VERSION 5.7 ;
  NOWIREEXTENSIONATPIN ON ;
  DIVIDERCHAR "/" ;
  BUSBITCHARS "[]" ;
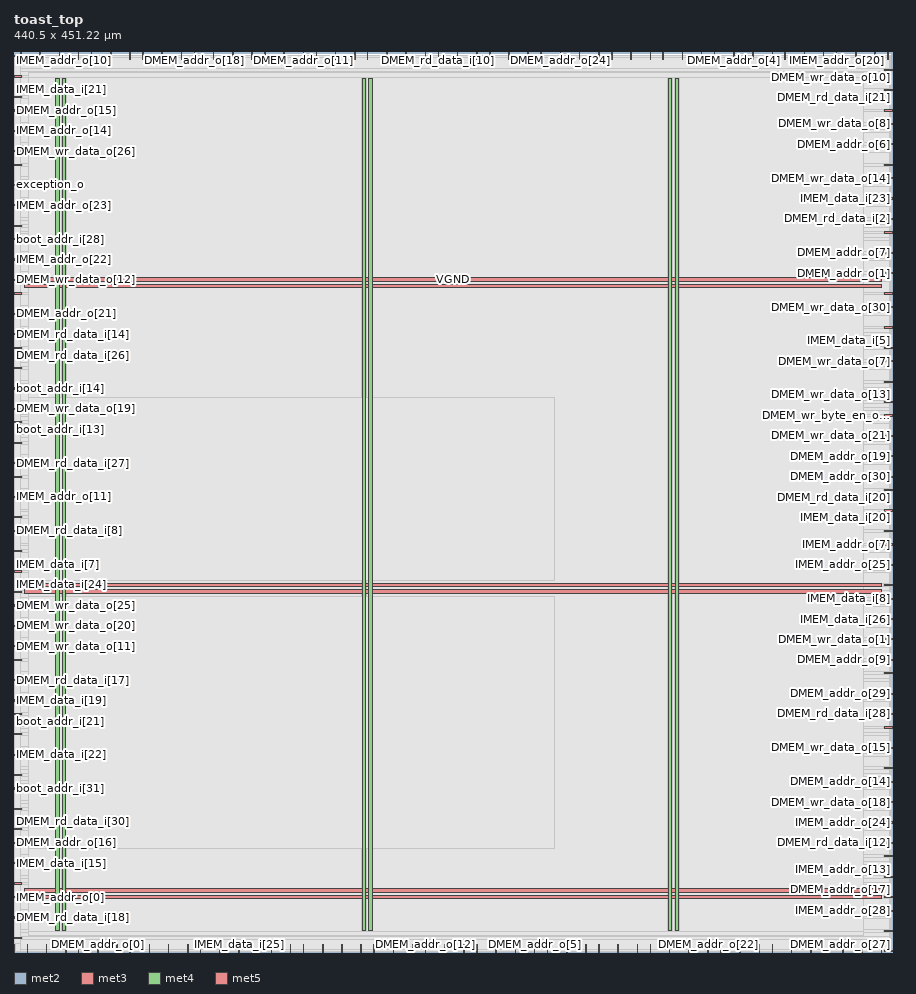
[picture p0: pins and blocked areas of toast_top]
MACRO toast_top
  CLASS BLOCK ;
  FOREIGN toast_top ;
  ORIGIN 0.000 0.000 ;
  SIZE 440.500 BY 451.220 ;
  PIN DMEM_addr_o[0]
    DIRECTION OUTPUT TRISTATE ;
    USE SIGNAL ;
    PORT
      LAYER met2 ;
        RECT 41.950 0.000 42.230 4.000 ;
    END
  END DMEM_addr_o[0]
  PIN DMEM_addr_o[10]
    DIRECTION OUTPUT TRISTATE ;
    USE SIGNAL ;
    PORT
      LAYER met2 ;
        RECT 177.190 447.220 177.470 451.220 ;
    END
  END DMEM_addr_o[10]
  PIN DMEM_addr_o[11]
    DIRECTION OUTPUT TRISTATE ;
    USE SIGNAL ;
    PORT
      LAYER met2 ;
        RECT 144.990 447.220 145.270 451.220 ;
    END
  END DMEM_addr_o[11]
  PIN DMEM_addr_o[12]
    DIRECTION OUTPUT TRISTATE ;
    USE SIGNAL ;
    PORT
      LAYER met2 ;
        RECT 206.170 0.000 206.450 4.000 ;
    END
  END DMEM_addr_o[12]
  PIN DMEM_addr_o[13]
    DIRECTION OUTPUT TRISTATE ;
    USE SIGNAL ;
    PORT
      LAYER met2 ;
        RECT 363.950 0.000 364.230 4.000 ;
    END
  END DMEM_addr_o[13]
  PIN DMEM_addr_o[14]
    DIRECTION OUTPUT TRISTATE ;
    USE SIGNAL ;
    PORT
      LAYER met3 ;
        RECT 436.500 85.040 440.500 85.640 ;
    END
  END DMEM_addr_o[14]
  PIN DMEM_addr_o[15]
    DIRECTION OUTPUT TRISTATE ;
    USE SIGNAL ;
    PORT
      LAYER met3 ;
        RECT 0.000 421.640 4.000 422.240 ;
    END
  END DMEM_addr_o[15]
  PIN DMEM_addr_o[16]
    DIRECTION OUTPUT TRISTATE ;
    USE SIGNAL ;
    PORT
      LAYER met3 ;
        RECT 0.000 54.440 4.000 55.040 ;
    END
  END DMEM_addr_o[16]
  PIN DMEM_addr_o[17]
    DIRECTION OUTPUT TRISTATE ;
    USE SIGNAL ;
    PORT
      LAYER met3 ;
        RECT 436.500 27.240 440.500 27.840 ;
    END
  END DMEM_addr_o[17]
  PIN DMEM_addr_o[18]
    DIRECTION OUTPUT TRISTATE ;
    USE SIGNAL ;
    PORT
      LAYER met2 ;
        RECT 90.250 447.220 90.530 451.220 ;
    END
  END DMEM_addr_o[18]
  PIN DMEM_addr_o[19]
    DIRECTION OUTPUT TRISTATE ;
    USE SIGNAL ;
    PORT
      LAYER met3 ;
        RECT 436.500 248.240 440.500 248.840 ;
    END
  END DMEM_addr_o[19]
  PIN DMEM_addr_o[1]
    DIRECTION OUTPUT TRISTATE ;
    USE SIGNAL ;
    PORT
      LAYER met3 ;
        RECT 436.500 340.040 440.500 340.640 ;
    END
  END DMEM_addr_o[1]
  PIN DMEM_addr_o[20]
    DIRECTION OUTPUT TRISTATE ;
    USE SIGNAL ;
    PORT
      LAYER met2 ;
        RECT 338.190 0.000 338.470 4.000 ;
    END
  END DMEM_addr_o[20]
  PIN DMEM_addr_o[21]
    DIRECTION OUTPUT TRISTATE ;
    USE SIGNAL ;
    PORT
      LAYER met3 ;
        RECT 0.000 319.640 4.000 320.240 ;
    END
  END DMEM_addr_o[21]
  PIN DMEM_addr_o[22]
    DIRECTION OUTPUT TRISTATE ;
    USE SIGNAL ;
    PORT
      LAYER met2 ;
        RECT 347.850 0.000 348.130 4.000 ;
    END
  END DMEM_addr_o[22]
  PIN DMEM_addr_o[23]
    DIRECTION OUTPUT TRISTATE ;
    USE SIGNAL ;
    PORT
      LAYER met2 ;
        RECT 144.990 0.000 145.270 4.000 ;
    END
  END DMEM_addr_o[23]
  PIN DMEM_addr_o[24]
    DIRECTION OUTPUT TRISTATE ;
    USE SIGNAL ;
    PORT
      LAYER met2 ;
        RECT 273.790 447.220 274.070 451.220 ;
    END
  END DMEM_addr_o[24]
  PIN DMEM_addr_o[25]
    DIRECTION OUTPUT TRISTATE ;
    USE SIGNAL ;
    PORT
      LAYER met3 ;
        RECT 0.000 394.440 4.000 395.040 ;
    END
  END DMEM_addr_o[25]
  PIN DMEM_addr_o[26]
    DIRECTION OUTPUT TRISTATE ;
    USE SIGNAL ;
    PORT
      LAYER met2 ;
        RECT 431.570 447.220 431.850 451.220 ;
    END
  END DMEM_addr_o[26]
  PIN DMEM_addr_o[27]
    DIRECTION OUTPUT TRISTATE ;
    USE SIGNAL ;
    PORT
      LAYER met2 ;
        RECT 415.470 0.000 415.750 4.000 ;
    END
  END DMEM_addr_o[27]
  PIN DMEM_addr_o[28]
    DIRECTION OUTPUT TRISTATE ;
    USE SIGNAL ;
    PORT
      LAYER met2 ;
        RECT 135.330 447.220 135.610 451.220 ;
    END
  END DMEM_addr_o[28]
  PIN DMEM_addr_o[29]
    DIRECTION OUTPUT TRISTATE ;
    USE SIGNAL ;
    PORT
      LAYER met3 ;
        RECT 436.500 129.240 440.500 129.840 ;
    END
  END DMEM_addr_o[29]
  PIN DMEM_addr_o[2]
    DIRECTION OUTPUT TRISTATE ;
    USE SIGNAL ;
    PORT
      LAYER met2 ;
        RECT 277.010 0.000 277.290 4.000 ;
    END
  END DMEM_addr_o[2]
  PIN DMEM_addr_o[30]
    DIRECTION OUTPUT TRISTATE ;
    USE SIGNAL ;
    PORT
      LAYER met3 ;
        RECT 436.500 238.040 440.500 238.640 ;
    END
  END DMEM_addr_o[30]
  PIN DMEM_addr_o[31]
    DIRECTION OUTPUT TRISTATE ;
    USE SIGNAL ;
    PORT
      LAYER met2 ;
        RECT 83.810 447.220 84.090 451.220 ;
    END
  END DMEM_addr_o[31]
  PIN DMEM_addr_o[3]
    DIRECTION OUTPUT TRISTATE ;
    USE SIGNAL ;
    PORT
      LAYER met2 ;
        RECT 22.630 447.220 22.910 451.220 ;
    END
  END DMEM_addr_o[3]
  PIN DMEM_addr_o[4]
    DIRECTION OUTPUT TRISTATE ;
    USE SIGNAL ;
    PORT
      LAYER met2 ;
        RECT 360.730 447.220 361.010 451.220 ;
    END
  END DMEM_addr_o[4]
  PIN DMEM_addr_o[5]
    DIRECTION OUTPUT TRISTATE ;
    USE SIGNAL ;
    PORT
      LAYER met2 ;
        RECT 260.910 0.000 261.190 4.000 ;
    END
  END DMEM_addr_o[5]
  PIN DMEM_addr_o[6]
    DIRECTION OUTPUT TRISTATE ;
    USE SIGNAL ;
    PORT
      LAYER met3 ;
        RECT 436.500 404.640 440.500 405.240 ;
    END
  END DMEM_addr_o[6]
  PIN DMEM_addr_o[7]
    DIRECTION OUTPUT TRISTATE ;
    USE SIGNAL ;
    PORT
      LAYER met3 ;
        RECT 436.500 350.240 440.500 350.840 ;
    END
  END DMEM_addr_o[7]
  PIN DMEM_addr_o[8]
    DIRECTION OUTPUT TRISTATE ;
    USE SIGNAL ;
    PORT
      LAYER met3 ;
        RECT 436.500 183.640 440.500 184.240 ;
    END
  END DMEM_addr_o[8]
  PIN DMEM_addr_o[9]
    DIRECTION OUTPUT TRISTATE ;
    USE SIGNAL ;
    PORT
      LAYER met3 ;
        RECT 436.500 146.240 440.500 146.840 ;
    END
  END DMEM_addr_o[9]
  PIN DMEM_rd_data_i[0]
    DIRECTION INPUT ;
    USE SIGNAL ;
    PORT
      LAYER met2 ;
        RECT 161.090 447.220 161.370 451.220 ;
    END
  END DMEM_rd_data_i[0]
  PIN DMEM_rd_data_i[10]
    DIRECTION INPUT ;
    USE SIGNAL ;
    PORT
      LAYER met2 ;
        RECT 212.610 447.220 212.890 451.220 ;
    END
  END DMEM_rd_data_i[10]
  PIN DMEM_rd_data_i[11]
    DIRECTION INPUT ;
    USE SIGNAL ;
    PORT
      LAYER met2 ;
        RECT 386.490 447.220 386.770 451.220 ;
    END
  END DMEM_rd_data_i[11]
  PIN DMEM_rd_data_i[12]
    DIRECTION INPUT ;
    USE SIGNAL ;
    PORT
      LAYER met3 ;
        RECT 436.500 54.440 440.500 55.040 ;
    END
  END DMEM_rd_data_i[12]
  PIN DMEM_rd_data_i[13]
    DIRECTION INPUT ;
    USE SIGNAL ;
    PORT
      LAYER met2 ;
        RECT 325.310 447.220 325.590 451.220 ;
    END
  END DMEM_rd_data_i[13]
  PIN DMEM_rd_data_i[14]
    DIRECTION INPUT ;
    USE SIGNAL ;
    PORT
      LAYER met3 ;
        RECT 0.000 309.440 4.000 310.040 ;
    END
  END DMEM_rd_data_i[14]
  PIN DMEM_rd_data_i[15]
    DIRECTION INPUT ;
    USE SIGNAL ;
    PORT
      LAYER met2 ;
        RECT 380.050 447.220 380.330 451.220 ;
    END
  END DMEM_rd_data_i[15]
  PIN DMEM_rd_data_i[16]
    DIRECTION INPUT ;
    USE SIGNAL ;
    PORT
      LAYER met2 ;
        RECT 293.110 0.000 293.390 4.000 ;
    END
  END DMEM_rd_data_i[16]
  PIN DMEM_rd_data_i[17]
    DIRECTION INPUT ;
    USE SIGNAL ;
    PORT
      LAYER met3 ;
        RECT 0.000 136.040 4.000 136.640 ;
    END
  END DMEM_rd_data_i[17]
  PIN DMEM_rd_data_i[18]
    DIRECTION INPUT ;
    USE SIGNAL ;
    PORT
      LAYER met3 ;
        RECT 0.000 17.040 4.000 17.640 ;
    END
  END DMEM_rd_data_i[18]
  PIN DMEM_rd_data_i[19]
    DIRECTION INPUT ;
    USE SIGNAL ;
    PORT
      LAYER met2 ;
        RECT 231.930 0.000 232.210 4.000 ;
    END
  END DMEM_rd_data_i[19]
  PIN DMEM_rd_data_i[1]
    DIRECTION INPUT ;
    USE SIGNAL ;
    PORT
      LAYER met2 ;
        RECT 128.890 0.000 129.170 4.000 ;
    END
  END DMEM_rd_data_i[1]
  PIN DMEM_rd_data_i[20]
    DIRECTION INPUT ;
    USE SIGNAL ;
    PORT
      LAYER met3 ;
        RECT 436.500 231.240 440.500 231.840 ;
    END
  END DMEM_rd_data_i[20]
  PIN DMEM_rd_data_i[21]
    DIRECTION INPUT ;
    USE SIGNAL ;
    PORT
      LAYER met3 ;
        RECT 436.500 431.840 440.500 432.440 ;
    END
  END DMEM_rd_data_i[21]
  PIN DMEM_rd_data_i[22]
    DIRECTION INPUT ;
    USE SIGNAL ;
    PORT
      LAYER met2 ;
        RECT 344.630 447.220 344.910 451.220 ;
    END
  END DMEM_rd_data_i[22]
  PIN DMEM_rd_data_i[23]
    DIRECTION INPUT ;
    USE SIGNAL ;
    PORT
      LAYER met3 ;
        RECT 0.000 448.840 4.000 449.440 ;
    END
  END DMEM_rd_data_i[23]
  PIN DMEM_rd_data_i[24]
    DIRECTION INPUT ;
    USE SIGNAL ;
    PORT
      LAYER met2 ;
        RECT 170.750 447.220 171.030 451.220 ;
    END
  END DMEM_rd_data_i[24]
  PIN DMEM_rd_data_i[25]
    DIRECTION INPUT ;
    USE SIGNAL ;
    PORT
      LAYER met2 ;
        RECT 434.790 0.000 435.070 4.000 ;
    END
  END DMEM_rd_data_i[25]
  PIN DMEM_rd_data_i[26]
    DIRECTION INPUT ;
    USE SIGNAL ;
    PORT
      LAYER met3 ;
        RECT 0.000 302.640 4.000 303.240 ;
    END
  END DMEM_rd_data_i[26]
  PIN DMEM_rd_data_i[27]
    DIRECTION INPUT ;
    USE SIGNAL ;
    PORT
      LAYER met3 ;
        RECT 0.000 244.840 4.000 245.440 ;
    END
  END DMEM_rd_data_i[27]
  PIN DMEM_rd_data_i[28]
    DIRECTION INPUT ;
    USE SIGNAL ;
    PORT
      LAYER met3 ;
        RECT 436.500 119.040 440.500 119.640 ;
    END
  END DMEM_rd_data_i[28]
  PIN DMEM_rd_data_i[29]
    DIRECTION INPUT ;
    USE SIGNAL ;
    PORT
      LAYER met3 ;
        RECT 0.000 6.840 4.000 7.440 ;
    END
  END DMEM_rd_data_i[29]
  PIN DMEM_rd_data_i[2]
    DIRECTION INPUT ;
    USE SIGNAL ;
    PORT
      LAYER met3 ;
        RECT 436.500 367.240 440.500 367.840 ;
    END
  END DMEM_rd_data_i[2]
  PIN DMEM_rd_data_i[30]
    DIRECTION INPUT ;
    USE SIGNAL ;
    PORT
      LAYER met3 ;
        RECT 0.000 61.240 4.000 61.840 ;
    END
  END DMEM_rd_data_i[30]
  PIN DMEM_rd_data_i[31]
    DIRECTION INPUT ;
    USE SIGNAL ;
    PORT
      LAYER met2 ;
        RECT 99.910 447.220 100.190 451.220 ;
    END
  END DMEM_rd_data_i[31]
  PIN DMEM_rd_data_i[3]
    DIRECTION INPUT ;
    USE SIGNAL ;
    PORT
      LAYER met2 ;
        RECT 93.470 0.000 93.750 4.000 ;
    END
  END DMEM_rd_data_i[3]
  PIN DMEM_rd_data_i[4]
    DIRECTION INPUT ;
    USE SIGNAL ;
    PORT
      LAYER met2 ;
        RECT 119.230 447.220 119.510 451.220 ;
    END
  END DMEM_rd_data_i[4]
  PIN DMEM_rd_data_i[5]
    DIRECTION INPUT ;
    USE SIGNAL ;
    PORT
      LAYER met2 ;
        RECT 399.370 0.000 399.650 4.000 ;
    END
  END DMEM_rd_data_i[5]
  PIN DMEM_rd_data_i[6]
    DIRECTION INPUT ;
    USE SIGNAL ;
    PORT
      LAYER met2 ;
        RECT 215.830 0.000 216.110 4.000 ;
    END
  END DMEM_rd_data_i[6]
  PIN DMEM_rd_data_i[7]
    DIRECTION INPUT ;
    USE SIGNAL ;
    PORT
      LAYER met2 ;
        RECT 125.670 447.220 125.950 451.220 ;
    END
  END DMEM_rd_data_i[7]
  PIN DMEM_rd_data_i[8]
    DIRECTION INPUT ;
    USE SIGNAL ;
    PORT
      LAYER met3 ;
        RECT 0.000 210.840 4.000 211.440 ;
    END
  END DMEM_rd_data_i[8]
  PIN DMEM_rd_data_i[9]
    DIRECTION INPUT ;
    USE SIGNAL ;
    PORT
      LAYER met2 ;
        RECT 32.290 0.000 32.570 4.000 ;
    END
  END DMEM_rd_data_i[9]
  PIN DMEM_rst_o
    DIRECTION OUTPUT TRISTATE ;
    USE SIGNAL ;
    PORT
      LAYER met3 ;
        RECT 0.000 200.640 4.000 201.240 ;
    END
  END DMEM_rst_o
  PIN DMEM_wr_byte_en_o[0]
    DIRECTION OUTPUT TRISTATE ;
    USE SIGNAL ;
    PORT
      LAYER met3 ;
        RECT 436.500 10.240 440.500 10.840 ;
    END
  END DMEM_wr_byte_en_o[0]
  PIN DMEM_wr_byte_en_o[1]
    DIRECTION OUTPUT TRISTATE ;
    USE SIGNAL ;
    PORT
      LAYER met3 ;
        RECT 436.500 268.640 440.500 269.240 ;
    END
  END DMEM_wr_byte_en_o[1]
  PIN DMEM_wr_byte_en_o[2]
    DIRECTION OUTPUT TRISTATE ;
    USE SIGNAL ;
    PORT
      LAYER met2 ;
        RECT 77.370 0.000 77.650 4.000 ;
    END
  END DMEM_wr_byte_en_o[2]
  PIN DMEM_wr_byte_en_o[3]
    DIRECTION OUTPUT TRISTATE ;
    USE SIGNAL ;
    PORT
      LAYER met2 ;
        RECT 318.870 447.220 319.150 451.220 ;
    END
  END DMEM_wr_byte_en_o[3]
  PIN DMEM_wr_data_o[0]
    DIRECTION OUTPUT TRISTATE ;
    USE SIGNAL ;
    PORT
      LAYER met2 ;
        RECT 109.570 447.220 109.850 451.220 ;
    END
  END DMEM_wr_data_o[0]
  PIN DMEM_wr_data_o[10]
    DIRECTION OUTPUT TRISTATE ;
    USE SIGNAL ;
    PORT
      LAYER met3 ;
        RECT 436.500 442.040 440.500 442.640 ;
    END
  END DMEM_wr_data_o[10]
  PIN DMEM_wr_data_o[11]
    DIRECTION OUTPUT TRISTATE ;
    USE SIGNAL ;
    PORT
      LAYER met3 ;
        RECT 0.000 153.040 4.000 153.640 ;
    END
  END DMEM_wr_data_o[11]
  PIN DMEM_wr_data_o[12]
    DIRECTION OUTPUT TRISTATE ;
    USE SIGNAL ;
    PORT
      LAYER met3 ;
        RECT 0.000 336.640 4.000 337.240 ;
    END
  END DMEM_wr_data_o[12]
  PIN DMEM_wr_data_o[13]
    DIRECTION OUTPUT TRISTATE ;
    USE SIGNAL ;
    PORT
      LAYER met3 ;
        RECT 436.500 275.440 440.500 276.040 ;
    END
  END DMEM_wr_data_o[13]
  PIN DMEM_wr_data_o[14]
    DIRECTION OUTPUT TRISTATE ;
    USE SIGNAL ;
    PORT
      LAYER met3 ;
        RECT 436.500 387.640 440.500 388.240 ;
    END
  END DMEM_wr_data_o[14]
  PIN DMEM_wr_data_o[15]
    DIRECTION OUTPUT TRISTATE ;
    USE SIGNAL ;
    PORT
      LAYER met3 ;
        RECT 436.500 102.040 440.500 102.640 ;
    END
  END DMEM_wr_data_o[15]
  PIN DMEM_wr_data_o[16]
    DIRECTION OUTPUT TRISTATE ;
    USE SIGNAL ;
    PORT
      LAYER met2 ;
        RECT 354.290 0.000 354.570 4.000 ;
    END
  END DMEM_wr_data_o[16]
  PIN DMEM_wr_data_o[17]
    DIRECTION OUTPUT TRISTATE ;
    USE SIGNAL ;
    PORT
      LAYER met3 ;
        RECT 0.000 292.440 4.000 293.040 ;
    END
  END DMEM_wr_data_o[17]
  PIN DMEM_wr_data_o[18]
    DIRECTION OUTPUT TRISTATE ;
    USE SIGNAL ;
    PORT
      LAYER met3 ;
        RECT 436.500 74.840 440.500 75.440 ;
    END
  END DMEM_wr_data_o[18]
  PIN DMEM_wr_data_o[19]
    DIRECTION OUTPUT TRISTATE ;
    USE SIGNAL ;
    PORT
      LAYER met3 ;
        RECT 0.000 272.040 4.000 272.640 ;
    END
  END DMEM_wr_data_o[19]
  PIN DMEM_wr_data_o[1]
    DIRECTION OUTPUT TRISTATE ;
    USE SIGNAL ;
    PORT
      LAYER met3 ;
        RECT 436.500 156.440 440.500 157.040 ;
    END
  END DMEM_wr_data_o[1]
  PIN DMEM_wr_data_o[20]
    DIRECTION OUTPUT TRISTATE ;
    USE SIGNAL ;
    PORT
      LAYER met3 ;
        RECT 0.000 163.240 4.000 163.840 ;
    END
  END DMEM_wr_data_o[20]
  PIN DMEM_wr_data_o[21]
    DIRECTION OUTPUT TRISTATE ;
    USE SIGNAL ;
    PORT
      LAYER met3 ;
        RECT 436.500 258.440 440.500 259.040 ;
    END
  END DMEM_wr_data_o[21]
  PIN DMEM_wr_data_o[22]
    DIRECTION OUTPUT TRISTATE ;
    USE SIGNAL ;
    PORT
      LAYER met2 ;
        RECT 438.010 447.220 438.290 451.220 ;
    END
  END DMEM_wr_data_o[22]
  PIN DMEM_wr_data_o[23]
    DIRECTION OUTPUT TRISTATE ;
    USE SIGNAL ;
    PORT
      LAYER met2 ;
        RECT 334.970 447.220 335.250 451.220 ;
    END
  END DMEM_wr_data_o[23]
  PIN DMEM_wr_data_o[24]
    DIRECTION OUTPUT TRISTATE ;
    USE SIGNAL ;
    PORT
      LAYER met2 ;
        RECT 138.550 0.000 138.830 4.000 ;
    END
  END DMEM_wr_data_o[24]
  PIN DMEM_wr_data_o[25]
    DIRECTION OUTPUT TRISTATE ;
    USE SIGNAL ;
    PORT
      LAYER met3 ;
        RECT 0.000 173.440 4.000 174.040 ;
    END
  END DMEM_wr_data_o[25]
  PIN DMEM_wr_data_o[26]
    DIRECTION OUTPUT TRISTATE ;
    USE SIGNAL ;
    PORT
      LAYER met3 ;
        RECT 0.000 401.240 4.000 401.840 ;
    END
  END DMEM_wr_data_o[26]
  PIN DMEM_wr_data_o[27]
    DIRECTION OUTPUT TRISTATE ;
    USE SIGNAL ;
    PORT
      LAYER met2 ;
        RECT 248.030 447.220 248.310 451.220 ;
    END
  END DMEM_wr_data_o[27]
  PIN DMEM_wr_data_o[28]
    DIRECTION OUTPUT TRISTATE ;
    USE SIGNAL ;
    PORT
      LAYER met2 ;
        RECT 370.390 447.220 370.670 451.220 ;
    END
  END DMEM_wr_data_o[28]
  PIN DMEM_wr_data_o[29]
    DIRECTION OUTPUT TRISTATE ;
    USE SIGNAL ;
    PORT
      LAYER met2 ;
        RECT 58.050 447.220 58.330 451.220 ;
    END
  END DMEM_wr_data_o[29]
  PIN DMEM_wr_data_o[2]
    DIRECTION OUTPUT TRISTATE ;
    USE SIGNAL ;
    PORT
      LAYER met2 ;
        RECT 186.850 447.220 187.130 451.220 ;
    END
  END DMEM_wr_data_o[2]
  PIN DMEM_wr_data_o[30]
    DIRECTION OUTPUT TRISTATE ;
    USE SIGNAL ;
    PORT
      LAYER met3 ;
        RECT 436.500 323.040 440.500 323.640 ;
    END
  END DMEM_wr_data_o[30]
  PIN DMEM_wr_data_o[31]
    DIRECTION OUTPUT TRISTATE ;
    USE SIGNAL ;
    PORT
      LAYER met2 ;
        RECT 238.370 447.220 238.650 451.220 ;
    END
  END DMEM_wr_data_o[31]
  PIN DMEM_wr_data_o[3]
    DIRECTION OUTPUT TRISTATE ;
    USE SIGNAL ;
    PORT
      LAYER met2 ;
        RECT 318.870 0.000 319.150 4.000 ;
    END
  END DMEM_wr_data_o[3]
  PIN DMEM_wr_data_o[4]
    DIRECTION OUTPUT TRISTATE ;
    USE SIGNAL ;
    PORT
      LAYER met3 ;
        RECT 436.500 360.440 440.500 361.040 ;
    END
  END DMEM_wr_data_o[4]
  PIN DMEM_wr_data_o[5]
    DIRECTION OUTPUT TRISTATE ;
    USE SIGNAL ;
    PORT
      LAYER met2 ;
        RECT 373.610 0.000 373.890 4.000 ;
    END
  END DMEM_wr_data_o[5]
  PIN DMEM_wr_data_o[6]
    DIRECTION OUTPUT TRISTATE ;
    USE SIGNAL ;
    PORT
      LAYER met2 ;
        RECT 48.390 447.220 48.670 451.220 ;
    END
  END DMEM_wr_data_o[6]
  PIN DMEM_wr_data_o[7]
    DIRECTION OUTPUT TRISTATE ;
    USE SIGNAL ;
    PORT
      LAYER met3 ;
        RECT 436.500 295.840 440.500 296.440 ;
    END
  END DMEM_wr_data_o[7]
  PIN DMEM_wr_data_o[8]
    DIRECTION OUTPUT TRISTATE ;
    USE SIGNAL ;
    PORT
      LAYER met3 ;
        RECT 436.500 414.840 440.500 415.440 ;
    END
  END DMEM_wr_data_o[8]
  PIN DMEM_wr_data_o[9]
    DIRECTION OUTPUT TRISTATE ;
    USE SIGNAL ;
    PORT
      LAYER met3 ;
        RECT 0.000 71.440 4.000 72.040 ;
    END
  END DMEM_wr_data_o[9]
  PIN IMEM_addr_o[0]
    DIRECTION OUTPUT TRISTATE ;
    USE SIGNAL ;
    PORT
      LAYER met3 ;
        RECT 0.000 27.240 4.000 27.840 ;
    END
  END IMEM_addr_o[0]
  PIN IMEM_addr_o[10]
    DIRECTION OUTPUT TRISTATE ;
    USE SIGNAL ;
    PORT
      LAYER met2 ;
        RECT 12.970 447.220 13.250 451.220 ;
    END
  END IMEM_addr_o[10]
  PIN IMEM_addr_o[11]
    DIRECTION OUTPUT TRISTATE ;
    USE SIGNAL ;
    PORT
      LAYER met3 ;
        RECT 0.000 227.840 4.000 228.440 ;
    END
  END IMEM_addr_o[11]
  PIN IMEM_addr_o[12]
    DIRECTION OUTPUT TRISTATE ;
    USE SIGNAL ;
    PORT
      LAYER met2 ;
        RECT 180.410 0.000 180.690 4.000 ;
    END
  END IMEM_addr_o[12]
  PIN IMEM_addr_o[13]
    DIRECTION OUTPUT TRISTATE ;
    USE SIGNAL ;
    PORT
      LAYER met3 ;
        RECT 436.500 37.440 440.500 38.040 ;
    END
  END IMEM_addr_o[13]
  PIN IMEM_addr_o[14]
    DIRECTION OUTPUT TRISTATE ;
    USE SIGNAL ;
    PORT
      LAYER met3 ;
        RECT 0.000 411.440 4.000 412.040 ;
    END
  END IMEM_addr_o[14]
  PIN IMEM_addr_o[15]
    DIRECTION OUTPUT TRISTATE ;
    USE SIGNAL ;
    PORT
      LAYER met2 ;
        RECT 286.670 0.000 286.950 4.000 ;
    END
  END IMEM_addr_o[15]
  PIN IMEM_addr_o[16]
    DIRECTION OUTPUT TRISTATE ;
    USE SIGNAL ;
    PORT
      LAYER met2 ;
        RECT 264.130 447.220 264.410 451.220 ;
    END
  END IMEM_addr_o[16]
  PIN IMEM_addr_o[17]
    DIRECTION OUTPUT TRISTATE ;
    USE SIGNAL ;
    PORT
      LAYER met2 ;
        RECT 283.450 447.220 283.730 451.220 ;
    END
  END IMEM_addr_o[17]
  PIN IMEM_addr_o[18]
    DIRECTION OUTPUT TRISTATE ;
    USE SIGNAL ;
    PORT
      LAYER met2 ;
        RECT 173.970 0.000 174.250 4.000 ;
    END
  END IMEM_addr_o[18]
  PIN IMEM_addr_o[19]
    DIRECTION OUTPUT TRISTATE ;
    USE SIGNAL ;
    PORT
      LAYER met2 ;
        RECT 231.930 447.220 232.210 451.220 ;
    END
  END IMEM_addr_o[19]
  PIN IMEM_addr_o[1]
    DIRECTION OUTPUT TRISTATE ;
    USE SIGNAL ;
    PORT
      LAYER met2 ;
        RECT 380.050 0.000 380.330 4.000 ;
    END
  END IMEM_addr_o[1]
  PIN IMEM_addr_o[20]
    DIRECTION OUTPUT TRISTATE ;
    USE SIGNAL ;
    PORT
      LAYER met2 ;
        RECT 412.250 447.220 412.530 451.220 ;
    END
  END IMEM_addr_o[20]
  PIN IMEM_addr_o[21]
    DIRECTION OUTPUT TRISTATE ;
    USE SIGNAL ;
    PORT
      LAYER met2 ;
        RECT 164.310 0.000 164.590 4.000 ;
    END
  END IMEM_addr_o[21]
  PIN IMEM_addr_o[22]
    DIRECTION OUTPUT TRISTATE ;
    USE SIGNAL ;
    PORT
      LAYER met3 ;
        RECT 0.000 346.840 4.000 347.440 ;
    END
  END IMEM_addr_o[22]
  PIN IMEM_addr_o[23]
    DIRECTION OUTPUT TRISTATE ;
    USE SIGNAL ;
    PORT
      LAYER met3 ;
        RECT 0.000 374.040 4.000 374.640 ;
    END
  END IMEM_addr_o[23]
  PIN IMEM_addr_o[24]
    DIRECTION OUTPUT TRISTATE ;
    USE SIGNAL ;
    PORT
      LAYER met3 ;
        RECT 436.500 64.640 440.500 65.240 ;
    END
  END IMEM_addr_o[24]
  PIN IMEM_addr_o[25]
    DIRECTION OUTPUT TRISTATE ;
    USE SIGNAL ;
    PORT
      LAYER met3 ;
        RECT 436.500 193.840 440.500 194.440 ;
    END
  END IMEM_addr_o[25]
  PIN IMEM_addr_o[26]
    DIRECTION OUTPUT TRISTATE ;
    USE SIGNAL ;
    PORT
      LAYER met2 ;
        RECT 119.230 0.000 119.510 4.000 ;
    END
  END IMEM_addr_o[26]
  PIN IMEM_addr_o[27]
    DIRECTION OUTPUT TRISTATE ;
    USE SIGNAL ;
    PORT
      LAYER met3 ;
        RECT 436.500 285.640 440.500 286.240 ;
    END
  END IMEM_addr_o[27]
  PIN IMEM_addr_o[28]
    DIRECTION OUTPUT TRISTATE ;
    USE SIGNAL ;
    PORT
      LAYER met3 ;
        RECT 436.500 20.440 440.500 21.040 ;
    END
  END IMEM_addr_o[28]
  PIN IMEM_addr_o[29]
    DIRECTION OUTPUT TRISTATE ;
    USE SIGNAL ;
    PORT
      LAYER met2 ;
        RECT 32.290 447.220 32.570 451.220 ;
    END
  END IMEM_addr_o[29]
  PIN IMEM_addr_o[2]
    DIRECTION OUTPUT TRISTATE ;
    USE SIGNAL ;
    PORT
      LAYER met3 ;
        RECT 0.000 363.840 4.000 364.440 ;
    END
  END IMEM_addr_o[2]
  PIN IMEM_addr_o[30]
    DIRECTION OUTPUT TRISTATE ;
    USE SIGNAL ;
    PORT
      LAYER met2 ;
        RECT 241.590 0.000 241.870 4.000 ;
    END
  END IMEM_addr_o[30]
  PIN IMEM_addr_o[31]
    DIRECTION OUTPUT TRISTATE ;
    USE SIGNAL ;
    PORT
      LAYER met2 ;
        RECT 103.130 0.000 103.410 4.000 ;
    END
  END IMEM_addr_o[31]
  PIN IMEM_addr_o[3]
    DIRECTION OUTPUT TRISTATE ;
    USE SIGNAL ;
    PORT
      LAYER met2 ;
        RECT 16.190 0.000 16.470 4.000 ;
    END
  END IMEM_addr_o[3]
  PIN IMEM_addr_o[4]
    DIRECTION OUTPUT TRISTATE ;
    USE SIGNAL ;
    PORT
      LAYER met2 ;
        RECT 328.530 0.000 328.810 4.000 ;
    END
  END IMEM_addr_o[4]
  PIN IMEM_addr_o[5]
    DIRECTION OUTPUT TRISTATE ;
    USE SIGNAL ;
    PORT
      LAYER met2 ;
        RECT 425.130 0.000 425.410 4.000 ;
    END
  END IMEM_addr_o[5]
  PIN IMEM_addr_o[6]
    DIRECTION OUTPUT TRISTATE ;
    USE SIGNAL ;
    PORT
      LAYER met2 ;
        RECT 396.150 447.220 396.430 451.220 ;
    END
  END IMEM_addr_o[6]
  PIN IMEM_addr_o[7]
    DIRECTION OUTPUT TRISTATE ;
    USE SIGNAL ;
    PORT
      LAYER met3 ;
        RECT 436.500 204.040 440.500 204.640 ;
    END
  END IMEM_addr_o[7]
  PIN IMEM_addr_o[8]
    DIRECTION OUTPUT TRISTATE ;
    USE SIGNAL ;
    PORT
      LAYER met2 ;
        RECT 151.430 447.220 151.710 451.220 ;
    END
  END IMEM_addr_o[8]
  PIN IMEM_addr_o[9]
    DIRECTION OUTPUT TRISTATE ;
    USE SIGNAL ;
    PORT
      LAYER met2 ;
        RECT 222.270 447.220 222.550 451.220 ;
    END
  END IMEM_addr_o[9]
  PIN IMEM_data_i[0]
    DIRECTION INPUT ;
    USE SIGNAL ;
    PORT
      LAYER met3 ;
        RECT 0.000 217.640 4.000 218.240 ;
    END
  END IMEM_data_i[0]
  PIN IMEM_data_i[10]
    DIRECTION INPUT ;
    USE SIGNAL ;
    PORT
      LAYER met3 ;
        RECT 0.000 238.040 4.000 238.640 ;
    END
  END IMEM_data_i[10]
  PIN IMEM_data_i[11]
    DIRECTION INPUT ;
    USE SIGNAL ;
    PORT
      LAYER met2 ;
        RECT 67.710 0.000 67.990 4.000 ;
    END
  END IMEM_data_i[11]
  PIN IMEM_data_i[12]
    DIRECTION INPUT ;
    USE SIGNAL ;
    PORT
      LAYER met3 ;
        RECT 0.000 146.240 4.000 146.840 ;
    END
  END IMEM_data_i[12]
  PIN IMEM_data_i[13]
    DIRECTION INPUT ;
    USE SIGNAL ;
    PORT
      LAYER met2 ;
        RECT 199.730 0.000 200.010 4.000 ;
    END
  END IMEM_data_i[13]
  PIN IMEM_data_i[14]
    DIRECTION INPUT ;
    USE SIGNAL ;
    PORT
      LAYER met3 ;
        RECT 436.500 394.440 440.500 395.040 ;
    END
  END IMEM_data_i[14]
  PIN IMEM_data_i[15]
    DIRECTION INPUT ;
    USE SIGNAL ;
    PORT
      LAYER met3 ;
        RECT 0.000 44.240 4.000 44.840 ;
    END
  END IMEM_data_i[15]
  PIN IMEM_data_i[16]
    DIRECTION INPUT ;
    USE SIGNAL ;
    PORT
      LAYER met2 ;
        RECT 257.690 447.220 257.970 451.220 ;
    END
  END IMEM_data_i[16]
  PIN IMEM_data_i[17]
    DIRECTION INPUT ;
    USE SIGNAL ;
    PORT
      LAYER met2 ;
        RECT 51.610 0.000 51.890 4.000 ;
    END
  END IMEM_data_i[17]
  PIN IMEM_data_i[18]
    DIRECTION INPUT ;
    USE SIGNAL ;
    PORT
      LAYER met3 ;
        RECT 436.500 139.440 440.500 140.040 ;
    END
  END IMEM_data_i[18]
  PIN IMEM_data_i[19]
    DIRECTION INPUT ;
    USE SIGNAL ;
    PORT
      LAYER met3 ;
        RECT 0.000 125.840 4.000 126.440 ;
    END
  END IMEM_data_i[19]
  PIN IMEM_data_i[1]
    DIRECTION INPUT ;
    USE SIGNAL ;
    PORT
      LAYER met2 ;
        RECT 74.150 447.220 74.430 451.220 ;
    END
  END IMEM_data_i[1]
  PIN IMEM_data_i[20]
    DIRECTION INPUT ;
    USE SIGNAL ;
    PORT
      LAYER met3 ;
        RECT 436.500 221.040 440.500 221.640 ;
    END
  END IMEM_data_i[20]
  PIN IMEM_data_i[21]
    DIRECTION INPUT ;
    USE SIGNAL ;
    PORT
      LAYER met3 ;
        RECT 0.000 428.440 4.000 429.040 ;
    END
  END IMEM_data_i[21]
  PIN IMEM_data_i[22]
    DIRECTION INPUT ;
    USE SIGNAL ;
    PORT
      LAYER met3 ;
        RECT 0.000 98.640 4.000 99.240 ;
    END
  END IMEM_data_i[22]
  PIN IMEM_data_i[23]
    DIRECTION INPUT ;
    USE SIGNAL ;
    PORT
      LAYER met3 ;
        RECT 436.500 377.440 440.500 378.040 ;
    END
  END IMEM_data_i[23]
  PIN IMEM_data_i[24]
    DIRECTION INPUT ;
    USE SIGNAL ;
    PORT
      LAYER met3 ;
        RECT 0.000 180.240 4.000 180.840 ;
    END
  END IMEM_data_i[24]
  PIN IMEM_data_i[25]
    DIRECTION INPUT ;
    USE SIGNAL ;
    PORT
      LAYER met2 ;
        RECT 112.790 0.000 113.070 4.000 ;
    END
  END IMEM_data_i[25]
  PIN IMEM_data_i[26]
    DIRECTION INPUT ;
    USE SIGNAL ;
    PORT
      LAYER met3 ;
        RECT 436.500 166.640 440.500 167.240 ;
    END
  END IMEM_data_i[26]
  PIN IMEM_data_i[27]
    DIRECTION INPUT ;
    USE SIGNAL ;
    PORT
      LAYER met2 ;
        RECT 302.770 0.000 303.050 4.000 ;
    END
  END IMEM_data_i[27]
  PIN IMEM_data_i[28]
    DIRECTION INPUT ;
    USE SIGNAL ;
    PORT
      LAYER met3 ;
        RECT 436.500 47.640 440.500 48.240 ;
    END
  END IMEM_data_i[28]
  PIN IMEM_data_i[29]
    DIRECTION INPUT ;
    USE SIGNAL ;
    PORT
      LAYER met2 ;
        RECT 3.310 447.220 3.590 451.220 ;
    END
  END IMEM_data_i[29]
  PIN IMEM_data_i[2]
    DIRECTION INPUT ;
    USE SIGNAL ;
    PORT
      LAYER met2 ;
        RECT 389.710 0.000 389.990 4.000 ;
    END
  END IMEM_data_i[2]
  PIN IMEM_data_i[30]
    DIRECTION INPUT ;
    USE SIGNAL ;
    PORT
      LAYER met2 ;
        RECT 58.050 0.000 58.330 4.000 ;
    END
  END IMEM_data_i[30]
  PIN IMEM_data_i[31]
    DIRECTION INPUT ;
    USE SIGNAL ;
    PORT
      LAYER met2 ;
        RECT 190.070 0.000 190.350 4.000 ;
    END
  END IMEM_data_i[31]
  PIN IMEM_data_i[3]
    DIRECTION INPUT ;
    USE SIGNAL ;
    PORT
      LAYER met3 ;
        RECT 436.500 112.240 440.500 112.840 ;
    END
  END IMEM_data_i[3]
  PIN IMEM_data_i[4]
    DIRECTION INPUT ;
    USE SIGNAL ;
    PORT
      LAYER met3 ;
        RECT 436.500 421.640 440.500 422.240 ;
    END
  END IMEM_data_i[4]
  PIN IMEM_data_i[5]
    DIRECTION INPUT ;
    USE SIGNAL ;
    PORT
      LAYER met3 ;
        RECT 436.500 302.640 440.500 303.240 ;
    END
  END IMEM_data_i[5]
  PIN IMEM_data_i[6]
    DIRECTION INPUT ;
    USE SIGNAL ;
    PORT
      LAYER met2 ;
        RECT 405.810 0.000 406.090 4.000 ;
    END
  END IMEM_data_i[6]
  PIN IMEM_data_i[7]
    DIRECTION INPUT ;
    USE SIGNAL ;
    PORT
      LAYER met3 ;
        RECT 0.000 190.440 4.000 191.040 ;
    END
  END IMEM_data_i[7]
  PIN IMEM_data_i[8]
    DIRECTION INPUT ;
    USE SIGNAL ;
    PORT
      LAYER met3 ;
        RECT 436.500 176.840 440.500 177.440 ;
    END
  END IMEM_data_i[8]
  PIN IMEM_data_i[9]
    DIRECTION INPUT ;
    USE SIGNAL ;
    PORT
      LAYER met2 ;
        RECT 6.530 0.000 6.810 4.000 ;
    END
  END IMEM_data_i[9]
  PIN VGND
    DIRECTION INOUT ;
    USE GROUND ;
    PORT
      LAYER met4 ;
        RECT 24.340 10.640 25.940 438.160 ;
    END
    PORT
      LAYER met4 ;
        RECT 177.940 10.640 179.540 438.160 ;
    END
    PORT
      LAYER met4 ;
        RECT 331.540 10.640 333.140 438.160 ;
    END
    PORT
      LAYER met5 ;
        RECT 5.280 30.030 434.940 31.630 ;
    END
    PORT
      LAYER met5 ;
        RECT 5.280 183.210 434.940 184.810 ;
    END
    PORT
      LAYER met5 ;
        RECT 5.280 336.390 434.940 337.990 ;
    END
  END VGND
  PIN VPWR
    DIRECTION INOUT ;
    USE POWER ;
    PORT
      LAYER met4 ;
        RECT 21.040 10.640 22.640 438.160 ;
    END
    PORT
      LAYER met4 ;
        RECT 174.640 10.640 176.240 438.160 ;
    END
    PORT
      LAYER met4 ;
        RECT 328.240 10.640 329.840 438.160 ;
    END
    PORT
      LAYER met5 ;
        RECT 5.280 26.730 434.940 28.330 ;
    END
    PORT
      LAYER met5 ;
        RECT 5.280 179.910 434.940 181.510 ;
    END
    PORT
      LAYER met5 ;
        RECT 5.280 333.090 434.940 334.690 ;
    END
  END VPWR
  PIN boot_addr_i[0]
    DIRECTION INPUT ;
    USE SIGNAL ;
    PORT
      LAYER met3 ;
        RECT 436.500 329.840 440.500 330.440 ;
    END
  END boot_addr_i[0]
  PIN boot_addr_i[10]
    DIRECTION INPUT ;
    USE SIGNAL ;
    PORT
      LAYER met2 ;
        RECT 421.910 447.220 422.190 451.220 ;
    END
  END boot_addr_i[10]
  PIN boot_addr_i[11]
    DIRECTION INPUT ;
    USE SIGNAL ;
    PORT
      LAYER met3 ;
        RECT 436.500 0.040 440.500 0.640 ;
    END
  END boot_addr_i[11]
  PIN boot_addr_i[12]
    DIRECTION INPUT ;
    USE SIGNAL ;
    PORT
      LAYER met2 ;
        RECT 405.810 447.220 406.090 451.220 ;
    END
  END boot_addr_i[12]
  PIN boot_addr_i[13]
    DIRECTION INPUT ;
    USE SIGNAL ;
    PORT
      LAYER met3 ;
        RECT 0.000 265.240 4.000 265.840 ;
    END
  END boot_addr_i[13]
  PIN boot_addr_i[14]
    DIRECTION INPUT ;
    USE SIGNAL ;
    PORT
      LAYER met3 ;
        RECT 0.000 282.240 4.000 282.840 ;
    END
  END boot_addr_i[14]
  PIN boot_addr_i[15]
    DIRECTION INPUT ;
    USE SIGNAL ;
    PORT
      LAYER met2 ;
        RECT 267.350 0.000 267.630 4.000 ;
    END
  END boot_addr_i[15]
  PIN boot_addr_i[16]
    DIRECTION INPUT ;
    USE SIGNAL ;
    PORT
      LAYER met2 ;
        RECT 0.090 0.000 0.370 4.000 ;
    END
  END boot_addr_i[16]
  PIN boot_addr_i[17]
    DIRECTION INPUT ;
    USE SIGNAL ;
    PORT
      LAYER met3 ;
        RECT 0.000 34.040 4.000 34.640 ;
    END
  END boot_addr_i[17]
  PIN boot_addr_i[18]
    DIRECTION INPUT ;
    USE SIGNAL ;
    PORT
      LAYER met3 ;
        RECT 0.000 329.840 4.000 330.440 ;
    END
  END boot_addr_i[18]
  PIN boot_addr_i[19]
    DIRECTION INPUT ;
    USE SIGNAL ;
    PORT
      LAYER met2 ;
        RECT 38.730 447.220 39.010 451.220 ;
    END
  END boot_addr_i[19]
  PIN boot_addr_i[1]
    DIRECTION INPUT ;
    USE SIGNAL ;
    PORT
      LAYER met2 ;
        RECT 206.170 447.220 206.450 451.220 ;
    END
  END boot_addr_i[1]
  PIN boot_addr_i[20]
    DIRECTION INPUT ;
    USE SIGNAL ;
    PORT
      LAYER met3 ;
        RECT 0.000 255.040 4.000 255.640 ;
    END
  END boot_addr_i[20]
  PIN boot_addr_i[21]
    DIRECTION INPUT ;
    USE SIGNAL ;
    PORT
      LAYER met3 ;
        RECT 0.000 119.040 4.000 119.640 ;
    END
  END boot_addr_i[21]
  PIN boot_addr_i[22]
    DIRECTION INPUT ;
    USE SIGNAL ;
    PORT
      LAYER met2 ;
        RECT 25.850 0.000 26.130 4.000 ;
    END
  END boot_addr_i[22]
  PIN boot_addr_i[23]
    DIRECTION INPUT ;
    USE SIGNAL ;
    PORT
      LAYER met2 ;
        RECT 293.110 447.220 293.390 451.220 ;
    END
  END boot_addr_i[23]
  PIN boot_addr_i[24]
    DIRECTION INPUT ;
    USE SIGNAL ;
    PORT
      LAYER met2 ;
        RECT 196.510 447.220 196.790 451.220 ;
    END
  END boot_addr_i[24]
  PIN boot_addr_i[25]
    DIRECTION INPUT ;
    USE SIGNAL ;
    PORT
      LAYER met2 ;
        RECT 225.490 0.000 225.770 4.000 ;
    END
  END boot_addr_i[25]
  PIN boot_addr_i[26]
    DIRECTION INPUT ;
    USE SIGNAL ;
    PORT
      LAYER met2 ;
        RECT 351.070 447.220 351.350 451.220 ;
    END
  END boot_addr_i[26]
  PIN boot_addr_i[27]
    DIRECTION INPUT ;
    USE SIGNAL ;
    PORT
      LAYER met3 ;
        RECT 436.500 91.840 440.500 92.440 ;
    END
  END boot_addr_i[27]
  PIN boot_addr_i[28]
    DIRECTION INPUT ;
    USE SIGNAL ;
    PORT
      LAYER met3 ;
        RECT 0.000 357.040 4.000 357.640 ;
    END
  END boot_addr_i[28]
  PIN boot_addr_i[29]
    DIRECTION INPUT ;
    USE SIGNAL ;
    PORT
      LAYER met3 ;
        RECT 0.000 88.440 4.000 89.040 ;
    END
  END boot_addr_i[29]
  PIN boot_addr_i[2]
    DIRECTION INPUT ;
    USE SIGNAL ;
    PORT
      LAYER met2 ;
        RECT 87.030 0.000 87.310 4.000 ;
    END
  END boot_addr_i[2]
  PIN boot_addr_i[30]
    DIRECTION INPUT ;
    USE SIGNAL ;
    PORT
      LAYER met2 ;
        RECT 154.650 0.000 154.930 4.000 ;
    END
  END boot_addr_i[30]
  PIN boot_addr_i[31]
    DIRECTION INPUT ;
    USE SIGNAL ;
    PORT
      LAYER met3 ;
        RECT 0.000 81.640 4.000 82.240 ;
    END
  END boot_addr_i[31]
  PIN boot_addr_i[3]
    DIRECTION INPUT ;
    USE SIGNAL ;
    PORT
      LAYER met3 ;
        RECT 436.500 312.840 440.500 313.440 ;
    END
  END boot_addr_i[3]
  PIN boot_addr_i[4]
    DIRECTION INPUT ;
    USE SIGNAL ;
    PORT
      LAYER met2 ;
        RECT 251.250 0.000 251.530 4.000 ;
    END
  END boot_addr_i[4]
  PIN boot_addr_i[5]
    DIRECTION INPUT ;
    USE SIGNAL ;
    PORT
      LAYER met2 ;
        RECT 309.210 447.220 309.490 451.220 ;
    END
  END boot_addr_i[5]
  PIN boot_addr_i[6]
    DIRECTION INPUT ;
    USE SIGNAL ;
    PORT
      LAYER met2 ;
        RECT 299.550 447.220 299.830 451.220 ;
    END
  END boot_addr_i[6]
  PIN boot_addr_i[7]
    DIRECTION INPUT ;
    USE SIGNAL ;
    PORT
      LAYER met3 ;
        RECT 0.000 438.640 4.000 439.240 ;
    END
  END boot_addr_i[7]
  PIN boot_addr_i[8]
    DIRECTION INPUT ;
    USE SIGNAL ;
    PORT
      LAYER met2 ;
        RECT 64.490 447.220 64.770 451.220 ;
    END
  END boot_addr_i[8]
  PIN boot_addr_i[9]
    DIRECTION INPUT ;
    USE SIGNAL ;
    PORT
      LAYER met2 ;
        RECT 312.430 0.000 312.710 4.000 ;
    END
  END boot_addr_i[9]
  PIN clk_i
    DIRECTION INPUT ;
    USE SIGNAL ;
    PORT
      LAYER met3 ;
        RECT 0.000 108.840 4.000 109.440 ;
    END
  END clk_i
  PIN exception_o
    DIRECTION OUTPUT TRISTATE ;
    USE SIGNAL ;
    PORT
      LAYER met3 ;
        RECT 0.000 384.240 4.000 384.840 ;
    END
  END exception_o
  PIN resetn_i
    DIRECTION INPUT ;
    USE SIGNAL ;
    PORT
      LAYER met3 ;
        RECT 436.500 210.840 440.500 211.440 ;
    END
  END resetn_i
  OBS
      LAYER li1 ;
        RECT 5.520 10.795 434.700 438.005 ;
      LAYER met1 ;
        RECT 0.070 7.180 439.690 441.620 ;
      LAYER met2 ;
        RECT 0.100 446.940 3.030 449.325 ;
        RECT 3.870 446.940 12.690 449.325 ;
        RECT 13.530 446.940 22.350 449.325 ;
        RECT 23.190 446.940 32.010 449.325 ;
        RECT 32.850 446.940 38.450 449.325 ;
        RECT 39.290 446.940 48.110 449.325 ;
        RECT 48.950 446.940 57.770 449.325 ;
        RECT 58.610 446.940 64.210 449.325 ;
        RECT 65.050 446.940 73.870 449.325 ;
        RECT 74.710 446.940 83.530 449.325 ;
        RECT 84.370 446.940 89.970 449.325 ;
        RECT 90.810 446.940 99.630 449.325 ;
        RECT 100.470 446.940 109.290 449.325 ;
        RECT 110.130 446.940 118.950 449.325 ;
        RECT 119.790 446.940 125.390 449.325 ;
        RECT 126.230 446.940 135.050 449.325 ;
        RECT 135.890 446.940 144.710 449.325 ;
        RECT 145.550 446.940 151.150 449.325 ;
        RECT 151.990 446.940 160.810 449.325 ;
        RECT 161.650 446.940 170.470 449.325 ;
        RECT 171.310 446.940 176.910 449.325 ;
        RECT 177.750 446.940 186.570 449.325 ;
        RECT 187.410 446.940 196.230 449.325 ;
        RECT 197.070 446.940 205.890 449.325 ;
        RECT 206.730 446.940 212.330 449.325 ;
        RECT 213.170 446.940 221.990 449.325 ;
        RECT 222.830 446.940 231.650 449.325 ;
        RECT 232.490 446.940 238.090 449.325 ;
        RECT 238.930 446.940 247.750 449.325 ;
        RECT 248.590 446.940 257.410 449.325 ;
        RECT 258.250 446.940 263.850 449.325 ;
        RECT 264.690 446.940 273.510 449.325 ;
        RECT 274.350 446.940 283.170 449.325 ;
        RECT 284.010 446.940 292.830 449.325 ;
        RECT 293.670 446.940 299.270 449.325 ;
        RECT 300.110 446.940 308.930 449.325 ;
        RECT 309.770 446.940 318.590 449.325 ;
        RECT 319.430 446.940 325.030 449.325 ;
        RECT 325.870 446.940 334.690 449.325 ;
        RECT 335.530 446.940 344.350 449.325 ;
        RECT 345.190 446.940 350.790 449.325 ;
        RECT 351.630 446.940 360.450 449.325 ;
        RECT 361.290 446.940 370.110 449.325 ;
        RECT 370.950 446.940 379.770 449.325 ;
        RECT 380.610 446.940 386.210 449.325 ;
        RECT 387.050 446.940 395.870 449.325 ;
        RECT 396.710 446.940 405.530 449.325 ;
        RECT 406.370 446.940 411.970 449.325 ;
        RECT 412.810 446.940 421.630 449.325 ;
        RECT 422.470 446.940 431.290 449.325 ;
        RECT 432.130 446.940 437.730 449.325 ;
        RECT 438.570 446.940 439.660 449.325 ;
        RECT 0.100 4.280 439.660 446.940 ;
        RECT 0.650 0.155 6.250 4.280 ;
        RECT 7.090 0.155 15.910 4.280 ;
        RECT 16.750 0.155 25.570 4.280 ;
        RECT 26.410 0.155 32.010 4.280 ;
        RECT 32.850 0.155 41.670 4.280 ;
        RECT 42.510 0.155 51.330 4.280 ;
        RECT 52.170 0.155 57.770 4.280 ;
        RECT 58.610 0.155 67.430 4.280 ;
        RECT 68.270 0.155 77.090 4.280 ;
        RECT 77.930 0.155 86.750 4.280 ;
        RECT 87.590 0.155 93.190 4.280 ;
        RECT 94.030 0.155 102.850 4.280 ;
        RECT 103.690 0.155 112.510 4.280 ;
        RECT 113.350 0.155 118.950 4.280 ;
        RECT 119.790 0.155 128.610 4.280 ;
        RECT 129.450 0.155 138.270 4.280 ;
        RECT 139.110 0.155 144.710 4.280 ;
        RECT 145.550 0.155 154.370 4.280 ;
        RECT 155.210 0.155 164.030 4.280 ;
        RECT 164.870 0.155 173.690 4.280 ;
        RECT 174.530 0.155 180.130 4.280 ;
        RECT 180.970 0.155 189.790 4.280 ;
        RECT 190.630 0.155 199.450 4.280 ;
        RECT 200.290 0.155 205.890 4.280 ;
        RECT 206.730 0.155 215.550 4.280 ;
        RECT 216.390 0.155 225.210 4.280 ;
        RECT 226.050 0.155 231.650 4.280 ;
        RECT 232.490 0.155 241.310 4.280 ;
        RECT 242.150 0.155 250.970 4.280 ;
        RECT 251.810 0.155 260.630 4.280 ;
        RECT 261.470 0.155 267.070 4.280 ;
        RECT 267.910 0.155 276.730 4.280 ;
        RECT 277.570 0.155 286.390 4.280 ;
        RECT 287.230 0.155 292.830 4.280 ;
        RECT 293.670 0.155 302.490 4.280 ;
        RECT 303.330 0.155 312.150 4.280 ;
        RECT 312.990 0.155 318.590 4.280 ;
        RECT 319.430 0.155 328.250 4.280 ;
        RECT 329.090 0.155 337.910 4.280 ;
        RECT 338.750 0.155 347.570 4.280 ;
        RECT 348.410 0.155 354.010 4.280 ;
        RECT 354.850 0.155 363.670 4.280 ;
        RECT 364.510 0.155 373.330 4.280 ;
        RECT 374.170 0.155 379.770 4.280 ;
        RECT 380.610 0.155 389.430 4.280 ;
        RECT 390.270 0.155 399.090 4.280 ;
        RECT 399.930 0.155 405.530 4.280 ;
        RECT 406.370 0.155 415.190 4.280 ;
        RECT 416.030 0.155 424.850 4.280 ;
        RECT 425.690 0.155 434.510 4.280 ;
        RECT 435.350 0.155 439.660 4.280 ;
      LAYER met3 ;
        RECT 4.400 448.440 438.775 449.305 ;
        RECT 3.285 443.040 438.775 448.440 ;
        RECT 3.285 441.640 436.100 443.040 ;
        RECT 3.285 439.640 438.775 441.640 ;
        RECT 4.400 438.240 438.775 439.640 ;
        RECT 3.285 432.840 438.775 438.240 ;
        RECT 3.285 431.440 436.100 432.840 ;
        RECT 3.285 429.440 438.775 431.440 ;
        RECT 4.400 428.040 438.775 429.440 ;
        RECT 3.285 422.640 438.775 428.040 ;
        RECT 4.400 421.240 436.100 422.640 ;
        RECT 3.285 415.840 438.775 421.240 ;
        RECT 3.285 414.440 436.100 415.840 ;
        RECT 3.285 412.440 438.775 414.440 ;
        RECT 4.400 411.040 438.775 412.440 ;
        RECT 3.285 405.640 438.775 411.040 ;
        RECT 3.285 404.240 436.100 405.640 ;
        RECT 3.285 402.240 438.775 404.240 ;
        RECT 4.400 400.840 438.775 402.240 ;
        RECT 3.285 395.440 438.775 400.840 ;
        RECT 4.400 394.040 436.100 395.440 ;
        RECT 3.285 388.640 438.775 394.040 ;
        RECT 3.285 387.240 436.100 388.640 ;
        RECT 3.285 385.240 438.775 387.240 ;
        RECT 4.400 383.840 438.775 385.240 ;
        RECT 3.285 378.440 438.775 383.840 ;
        RECT 3.285 377.040 436.100 378.440 ;
        RECT 3.285 375.040 438.775 377.040 ;
        RECT 4.400 373.640 438.775 375.040 ;
        RECT 3.285 368.240 438.775 373.640 ;
        RECT 3.285 366.840 436.100 368.240 ;
        RECT 3.285 364.840 438.775 366.840 ;
        RECT 4.400 363.440 438.775 364.840 ;
        RECT 3.285 361.440 438.775 363.440 ;
        RECT 3.285 360.040 436.100 361.440 ;
        RECT 3.285 358.040 438.775 360.040 ;
        RECT 4.400 356.640 438.775 358.040 ;
        RECT 3.285 351.240 438.775 356.640 ;
        RECT 3.285 349.840 436.100 351.240 ;
        RECT 3.285 347.840 438.775 349.840 ;
        RECT 4.400 346.440 438.775 347.840 ;
        RECT 3.285 341.040 438.775 346.440 ;
        RECT 3.285 339.640 436.100 341.040 ;
        RECT 3.285 337.640 438.775 339.640 ;
        RECT 4.400 336.240 438.775 337.640 ;
        RECT 3.285 330.840 438.775 336.240 ;
        RECT 4.400 329.440 436.100 330.840 ;
        RECT 3.285 324.040 438.775 329.440 ;
        RECT 3.285 322.640 436.100 324.040 ;
        RECT 3.285 320.640 438.775 322.640 ;
        RECT 4.400 319.240 438.775 320.640 ;
        RECT 3.285 313.840 438.775 319.240 ;
        RECT 3.285 312.440 436.100 313.840 ;
        RECT 3.285 310.440 438.775 312.440 ;
        RECT 4.400 309.040 438.775 310.440 ;
        RECT 3.285 303.640 438.775 309.040 ;
        RECT 4.400 302.240 436.100 303.640 ;
        RECT 3.285 296.840 438.775 302.240 ;
        RECT 3.285 295.440 436.100 296.840 ;
        RECT 3.285 293.440 438.775 295.440 ;
        RECT 4.400 292.040 438.775 293.440 ;
        RECT 3.285 286.640 438.775 292.040 ;
        RECT 3.285 285.240 436.100 286.640 ;
        RECT 3.285 283.240 438.775 285.240 ;
        RECT 4.400 281.840 438.775 283.240 ;
        RECT 3.285 276.440 438.775 281.840 ;
        RECT 3.285 275.040 436.100 276.440 ;
        RECT 3.285 273.040 438.775 275.040 ;
        RECT 4.400 271.640 438.775 273.040 ;
        RECT 3.285 269.640 438.775 271.640 ;
        RECT 3.285 268.240 436.100 269.640 ;
        RECT 3.285 266.240 438.775 268.240 ;
        RECT 4.400 264.840 438.775 266.240 ;
        RECT 3.285 259.440 438.775 264.840 ;
        RECT 3.285 258.040 436.100 259.440 ;
        RECT 3.285 256.040 438.775 258.040 ;
        RECT 4.400 254.640 438.775 256.040 ;
        RECT 3.285 249.240 438.775 254.640 ;
        RECT 3.285 247.840 436.100 249.240 ;
        RECT 3.285 245.840 438.775 247.840 ;
        RECT 4.400 244.440 438.775 245.840 ;
        RECT 3.285 239.040 438.775 244.440 ;
        RECT 4.400 237.640 436.100 239.040 ;
        RECT 3.285 232.240 438.775 237.640 ;
        RECT 3.285 230.840 436.100 232.240 ;
        RECT 3.285 228.840 438.775 230.840 ;
        RECT 4.400 227.440 438.775 228.840 ;
        RECT 3.285 222.040 438.775 227.440 ;
        RECT 3.285 220.640 436.100 222.040 ;
        RECT 3.285 218.640 438.775 220.640 ;
        RECT 4.400 217.240 438.775 218.640 ;
        RECT 3.285 211.840 438.775 217.240 ;
        RECT 4.400 210.440 436.100 211.840 ;
        RECT 3.285 205.040 438.775 210.440 ;
        RECT 3.285 203.640 436.100 205.040 ;
        RECT 3.285 201.640 438.775 203.640 ;
        RECT 4.400 200.240 438.775 201.640 ;
        RECT 3.285 194.840 438.775 200.240 ;
        RECT 3.285 193.440 436.100 194.840 ;
        RECT 3.285 191.440 438.775 193.440 ;
        RECT 4.400 190.040 438.775 191.440 ;
        RECT 3.285 184.640 438.775 190.040 ;
        RECT 3.285 183.240 436.100 184.640 ;
        RECT 3.285 181.240 438.775 183.240 ;
        RECT 4.400 179.840 438.775 181.240 ;
        RECT 3.285 177.840 438.775 179.840 ;
        RECT 3.285 176.440 436.100 177.840 ;
        RECT 3.285 174.440 438.775 176.440 ;
        RECT 4.400 173.040 438.775 174.440 ;
        RECT 3.285 167.640 438.775 173.040 ;
        RECT 3.285 166.240 436.100 167.640 ;
        RECT 3.285 164.240 438.775 166.240 ;
        RECT 4.400 162.840 438.775 164.240 ;
        RECT 3.285 157.440 438.775 162.840 ;
        RECT 3.285 156.040 436.100 157.440 ;
        RECT 3.285 154.040 438.775 156.040 ;
        RECT 4.400 152.640 438.775 154.040 ;
        RECT 3.285 147.240 438.775 152.640 ;
        RECT 4.400 145.840 436.100 147.240 ;
        RECT 3.285 140.440 438.775 145.840 ;
        RECT 3.285 139.040 436.100 140.440 ;
        RECT 3.285 137.040 438.775 139.040 ;
        RECT 4.400 135.640 438.775 137.040 ;
        RECT 3.285 130.240 438.775 135.640 ;
        RECT 3.285 128.840 436.100 130.240 ;
        RECT 3.285 126.840 438.775 128.840 ;
        RECT 4.400 125.440 438.775 126.840 ;
        RECT 3.285 120.040 438.775 125.440 ;
        RECT 4.400 118.640 436.100 120.040 ;
        RECT 3.285 113.240 438.775 118.640 ;
        RECT 3.285 111.840 436.100 113.240 ;
        RECT 3.285 109.840 438.775 111.840 ;
        RECT 4.400 108.440 438.775 109.840 ;
        RECT 3.285 103.040 438.775 108.440 ;
        RECT 3.285 101.640 436.100 103.040 ;
        RECT 3.285 99.640 438.775 101.640 ;
        RECT 4.400 98.240 438.775 99.640 ;
        RECT 3.285 92.840 438.775 98.240 ;
        RECT 3.285 91.440 436.100 92.840 ;
        RECT 3.285 89.440 438.775 91.440 ;
        RECT 4.400 88.040 438.775 89.440 ;
        RECT 3.285 86.040 438.775 88.040 ;
        RECT 3.285 84.640 436.100 86.040 ;
        RECT 3.285 82.640 438.775 84.640 ;
        RECT 4.400 81.240 438.775 82.640 ;
        RECT 3.285 75.840 438.775 81.240 ;
        RECT 3.285 74.440 436.100 75.840 ;
        RECT 3.285 72.440 438.775 74.440 ;
        RECT 4.400 71.040 438.775 72.440 ;
        RECT 3.285 65.640 438.775 71.040 ;
        RECT 3.285 64.240 436.100 65.640 ;
        RECT 3.285 62.240 438.775 64.240 ;
        RECT 4.400 60.840 438.775 62.240 ;
        RECT 3.285 55.440 438.775 60.840 ;
        RECT 4.400 54.040 436.100 55.440 ;
        RECT 3.285 48.640 438.775 54.040 ;
        RECT 3.285 47.240 436.100 48.640 ;
        RECT 3.285 45.240 438.775 47.240 ;
        RECT 4.400 43.840 438.775 45.240 ;
        RECT 3.285 38.440 438.775 43.840 ;
        RECT 3.285 37.040 436.100 38.440 ;
        RECT 3.285 35.040 438.775 37.040 ;
        RECT 4.400 33.640 438.775 35.040 ;
        RECT 3.285 28.240 438.775 33.640 ;
        RECT 4.400 26.840 436.100 28.240 ;
        RECT 3.285 21.440 438.775 26.840 ;
        RECT 3.285 20.040 436.100 21.440 ;
        RECT 3.285 18.040 438.775 20.040 ;
        RECT 4.400 16.640 438.775 18.040 ;
        RECT 3.285 11.240 438.775 16.640 ;
        RECT 3.285 9.840 436.100 11.240 ;
        RECT 3.285 7.840 438.775 9.840 ;
        RECT 4.400 6.440 438.775 7.840 ;
        RECT 3.285 1.040 438.775 6.440 ;
        RECT 3.285 0.175 436.100 1.040 ;
      LAYER met4 ;
        RECT 7.230 438.560 425.665 441.145 ;
        RECT 7.230 10.240 20.640 438.560 ;
        RECT 23.040 10.240 23.940 438.560 ;
        RECT 26.340 10.240 174.240 438.560 ;
        RECT 176.640 10.240 177.540 438.560 ;
        RECT 179.940 10.240 327.840 438.560 ;
        RECT 330.240 10.240 331.140 438.560 ;
        RECT 333.540 10.240 425.665 438.560 ;
        RECT 7.230 8.335 425.665 10.240 ;
      LAYER met5 ;
        RECT 7.020 186.410 270.820 277.900 ;
        RECT 7.020 51.900 270.820 178.310 ;
  END
END toast_top
END LIBRARY

